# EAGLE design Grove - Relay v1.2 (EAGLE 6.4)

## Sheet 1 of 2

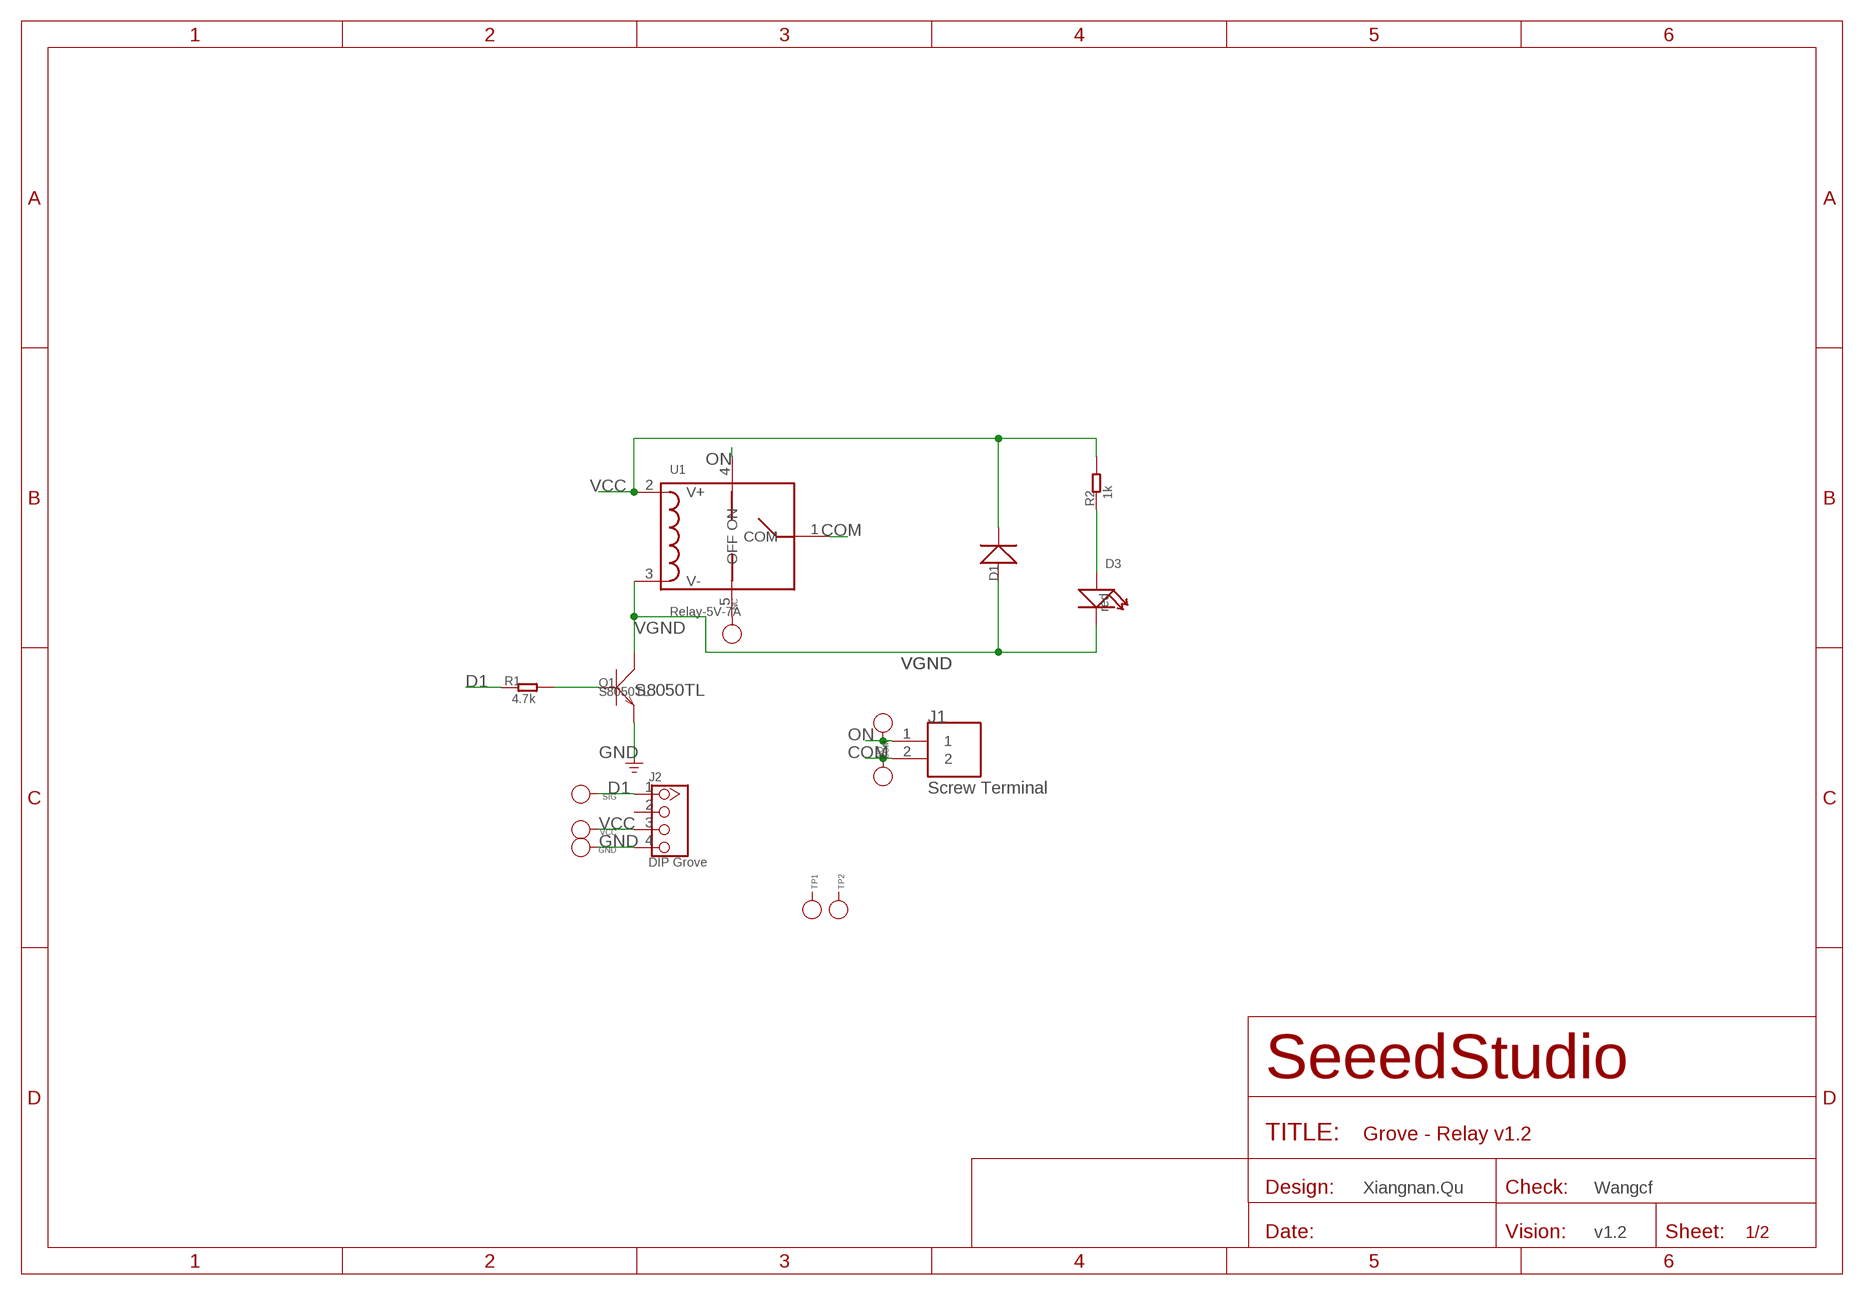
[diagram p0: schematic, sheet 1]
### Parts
COM  PAD-TEST-POINT'4545'  [TP_4545]
D1  D'1N4148-SMD'  [LL-34]
D3  red  LED'0603'  [LED-0603]
GND  PAD-TEST-POINT'4545'  [TP_4545]
J1  Screw Terminal  CON2  [CON2]
J2  DIP Grove  TWIG_2.0  [2.0_1X4]
NC  PAD-TEST-POINT'4545'  [TP_4545]
NO  PAD-TEST-POINT'4545'  [TP_4545]
Q1  S8050TL  TRANSISTOR-NPN-SOT23  [SOT23]
R1  4.7k  R-0603  [R0603]
R2  1k  R-0603  [R0603]
SIG  PAD-TEST-POINT'4545'  [TP_4545]
TP1  PAD-TEST-POINT'4545'  [TP_4545]
TP2  PAD-TEST-POINT'4545'  [TP_4545]
U1  Relay-5V-7A  RELAY  [RELAY]
VCC  PAD-TEST-POINT'4545'  [TP_4545]

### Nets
COM: COM.T J1.2 U1.1(COM)
D1: J2.1 R1.1 SIG.T
GND: GND.T J2.4 Q1.2(E)
N$1: D3.+ R2.1
N$2: Q1.1(B) R1.2
N$3: NC.T U1.5(OFF)
ON: J1.1 NO.T U1.4(ON)
VCC: D1.C(-) J2.3 R2.2 U1.2(V+) VCC.T
VGND: D1.A(+) D3.- Q1.3(C) U1.3(V-)
Unconnected: J2.2 TP1.T TP2.T

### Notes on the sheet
- S8050TL
- Xiangnan.Qu | Wangcf
- v1.2

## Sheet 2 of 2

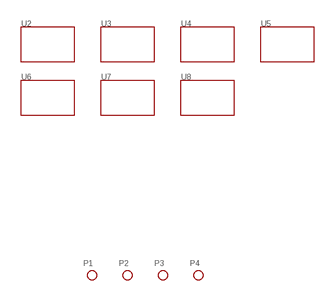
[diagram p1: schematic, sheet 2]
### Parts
P1  PAD-MARK  [ROUND-MARK-1.0]
P2  PAD-MARK  [ROUND-MARK-1.0]
P3  PAD-MARK  [ROUND-MARK-1.0]
P4  PAD-MARK  [ROUND-MARK-1.0]
U2  TWIG'2U'  [GROVE-TEST-PLATFORM]
U3  TWIG'2U'  [GROVE-TEST-PLATFORM]
U4  TWIG'2U'  [GROVE-TEST-PLATFORM]
U5  TWIG'2U'  [GROVE-TEST-PLATFORM]
U6  TWIG'2U'  [GROVE-TEST-PLATFORM]
U7  TWIG'2U'  [GROVE-TEST-PLATFORM]
U8  TWIG'2U'  [GROVE-TEST-PLATFORM]

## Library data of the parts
COM GND NC NO SIG TP1 TP2 VCC = Discrete:PAD-TEST-POINT; PARTNO: DNP
D1 = Discrete:D*
D3 = Discrete:LED*
J1 = seeedleo:CON2
J2 = CONNECTER:TWIG_2.0
P1-P4 = Discrete:PAD-MARK; PARTNO: DNP
Q1 = Discrete:TRANSISTOR-NPN*: NPN audion
R1 R2 = Discrete:R*
U1 = Seeed:RELAY
U2-U8 = template:TWIG

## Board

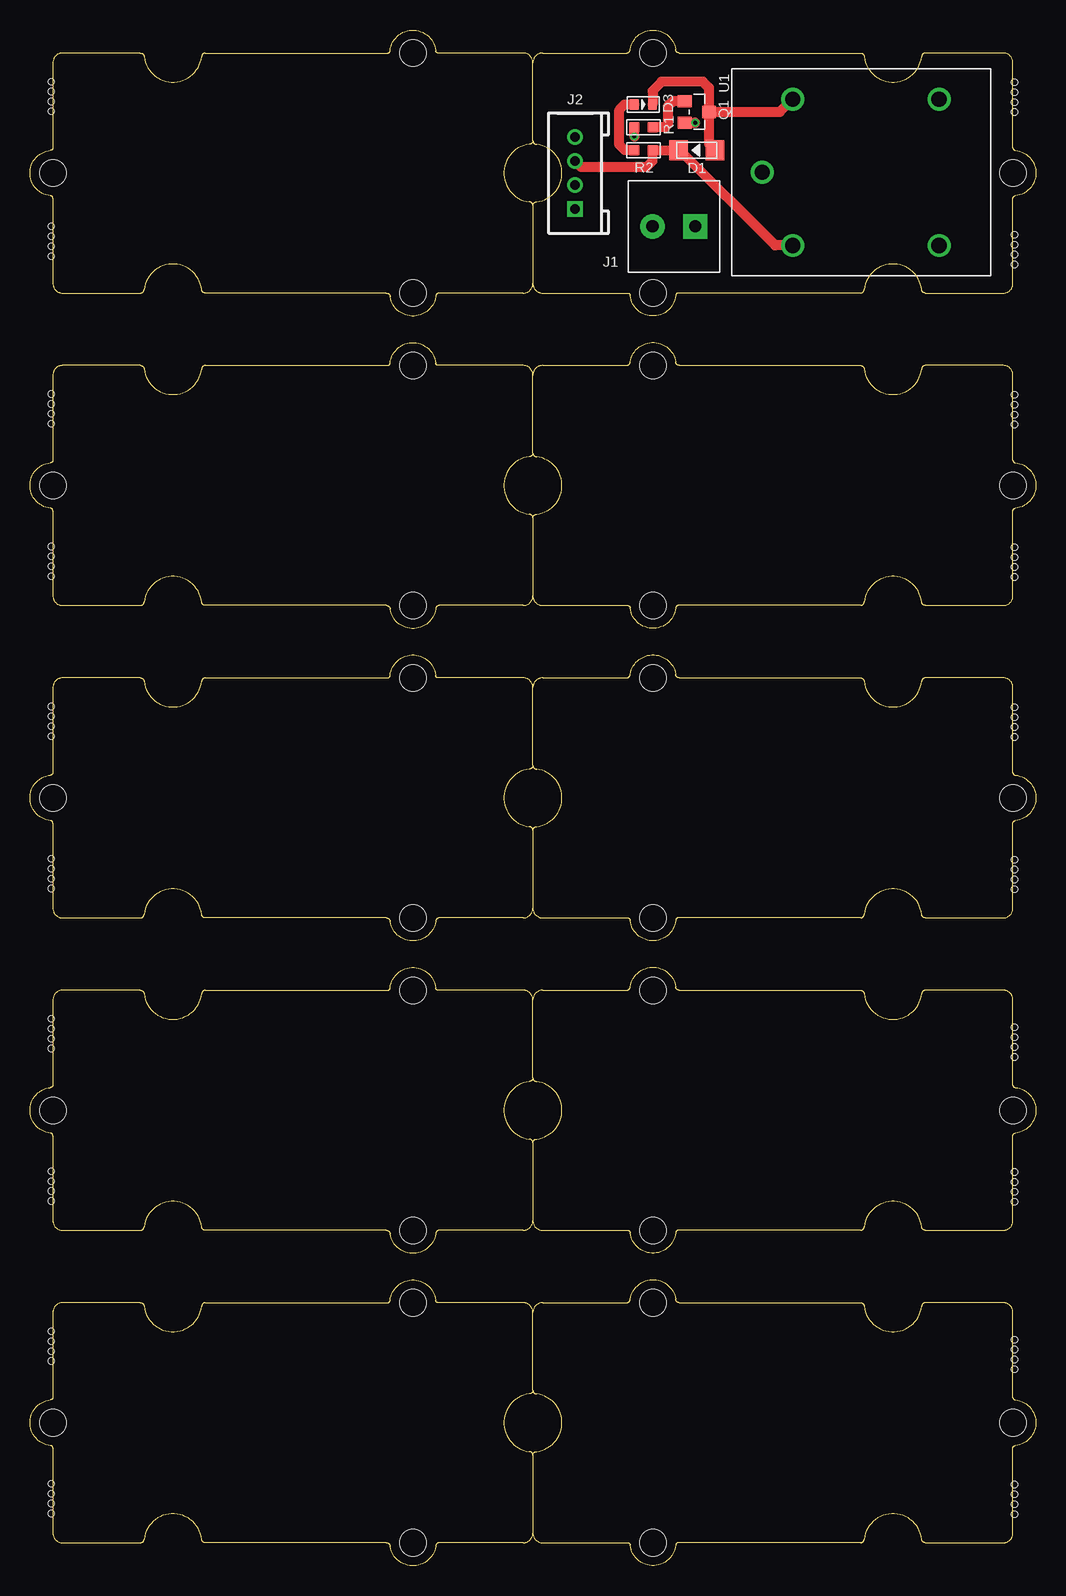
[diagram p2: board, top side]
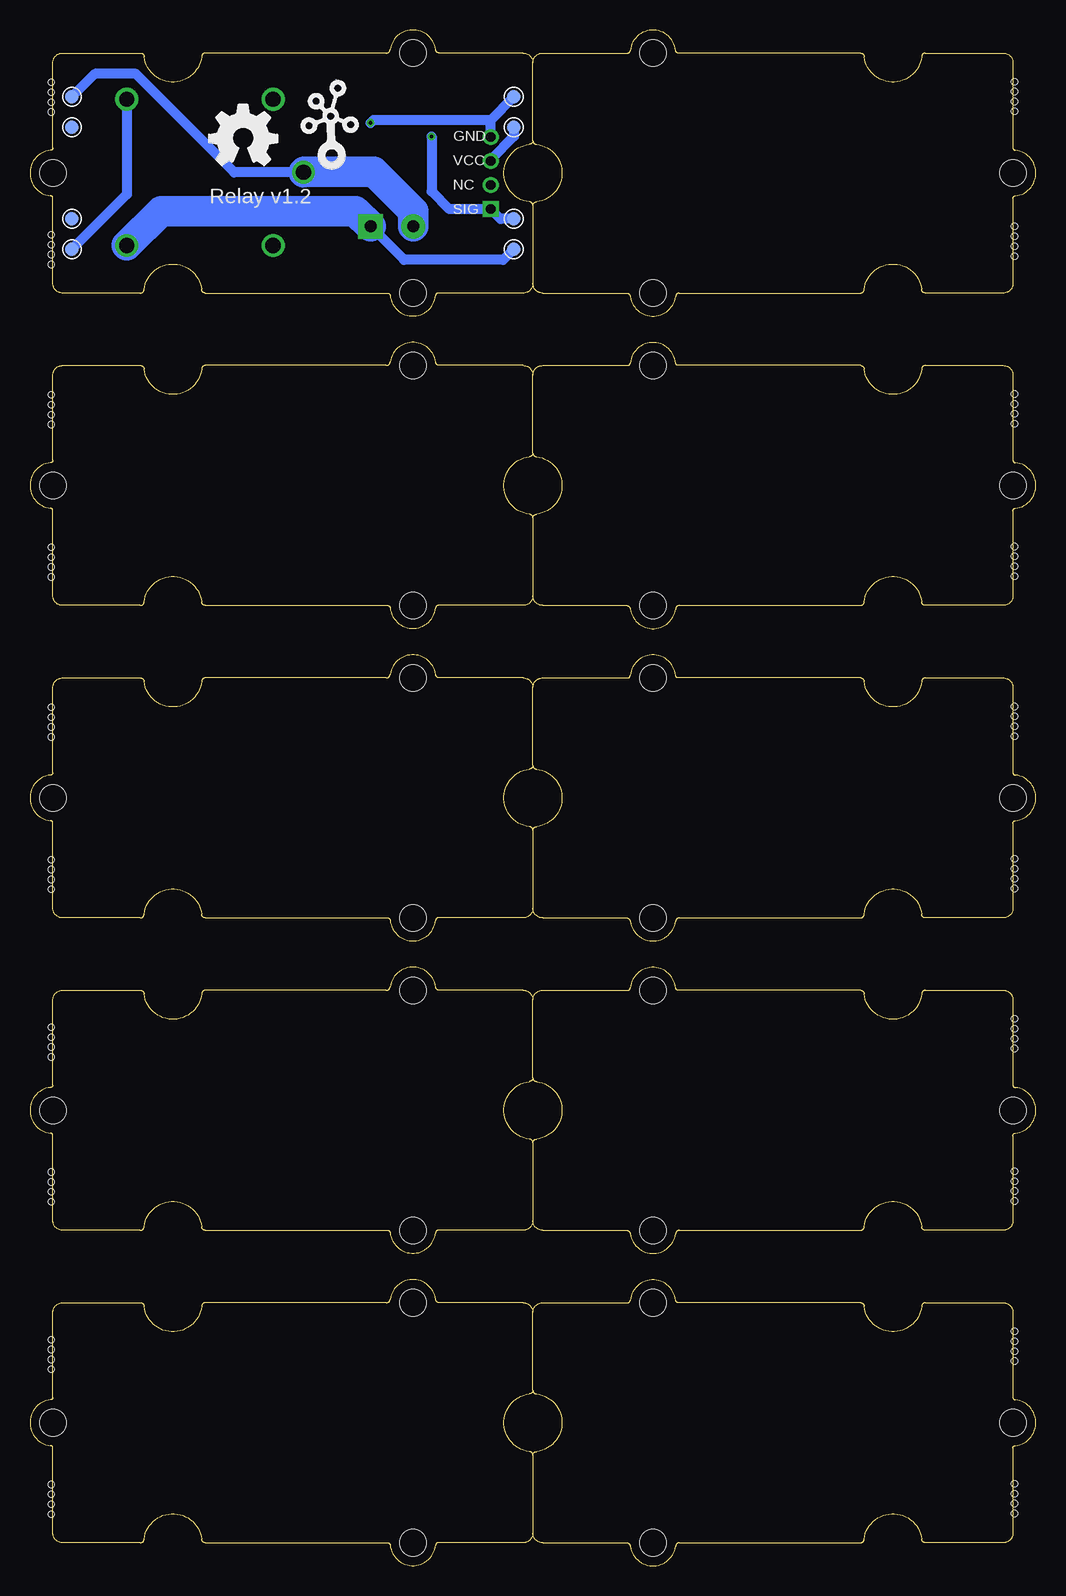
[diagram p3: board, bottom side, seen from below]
Size 83.82 x 127.98 mm. Coordinates in mm from the lower left corner, seen from the top.
Copper layers (1*16): Top 0.035mm / dielectric 1.5mm / Bottom 0.035mm
Design rules "default": minimum track width 6mil, minimum drill 12mil, track to track 6mil, track to pad 6mil, pad to pad 6mil, via to via 6mil, smd to smd 0mil, copper to edge 10mil, drill to drill 10mil, minimum pad ring 10mil, minimum via ring 6mil, stop-mask expansion 2mil, vias tented up to drill 100mil, thermal gap 10mil
Holes 0.5 mm at 1.78,32.88 1.78,30.4 1.78,31.23 1.78,32.05 1.78,45.58 1.78,43.1 1.78,43.93 1.78,44.75 1.78,58.91 1.78,56.43 1.78,57.26 1.78,58.09 1.78,71.61 1.78,69.13 1.78,69.96 1.78,70.79 1.78,84.95 1.78,82.47 1.78,83.3 1.78,84.12 1.78,97.65 1.78,95.17 1.78,96 1.78,96.82 1.78,111.62 1.78,109.14 1.78,109.97 1.78,110.79 1.78,123.68 1.78,121.2 1.78,122.03 1.78,122.86 82.04,121.14 82.04,123.62 82.04,122.79 82.04,121.97 82.04,108.44 82.04,110.92 82.04,110.09 82.04,109.27 82.04,95.11 82.04,97.58 82.04,96.76 82.04,95.93 82.04,82.41 82.04,84.88 82.04,84.06 82.04,83.23 82.04,69.07 82.04,71.55 82.04,70.72 82.04,69.9 82.04,56.37 82.04,58.85 82.04,58.02 82.04,57.2 82.04,42.4 82.04,44.88 82.04,44.05 82.04,43.23 82.04,30.34 82.04,32.81 82.04,31.99 82.04,31.16 1.78,6.84 1.78,4.36 1.78,5.19 1.78,6.02 1.78,19.54 1.78,17.06 1.78,17.89 1.78,18.72 82.04,16.37 82.04,18.84 82.04,18.02 82.04,17.19 82.04,4.3 82.04,6.78 82.04,5.95 82.04,5.13
Holes 1.91 mm at -4.13,2.4 87.95,2.4 87.95,125.59 -4.13,125.59

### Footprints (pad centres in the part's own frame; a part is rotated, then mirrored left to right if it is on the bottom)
TP_4545 = smd 1.143 x 1.143: T 0,0
LL-34 = smd 1.524 x 1.676: A -1.524,0; C 1.524,0
LED-0603 = smd 0.762 x 0.889: + -0.762,0; - 0.762,0
CON2 = drill 1.016 pad 2.032 square: 1 0,1.778 | drill 1.016 pad 2.032: 2 0,-1.778
2.0_1X4 = drill 0.8 pad 1.27 square: 1 -3,0 | drill 0.8 pad 1.27: 2 -1,0; 3 1,0; 4 3,0
ROUND-MARK-1.0 = smd 1.016 x 1.016: P$1 0,0
SOT23 = smd 1.016 x 1.143: 1 -0.889,-1.016; 2 0.889,-1.016; 3 0,1.016
R0603 = smd 0.889 x 0.889: 1 -0.762,0; 2 0.762,0
RELAY = drill 1.27: 1 -2.54,-6.096; 2 0,-12.192; 3 0,0; 4 12.192,-12.192; 5 12.192,0
GROVE-TEST-PLATFORM = hole 2.2: -10,-10; -10,10; 20,0

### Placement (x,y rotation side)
COM  80.33,122.41 0 bottom
D1  55.56,117.97 180 top
D3  51.12,121.78 0 top
GND  43.5,122.41 0 bottom
J1  53.66,111.62 270 top
J2  45.43,116.06 90 top
NC  80.33,109.71 0 bottom
NO  43.5,109.71 0 bottom
P1  not placed on the board
P2  not placed on the board
P3  not placed on the board
P4  not placed on the board
Q1  55.58,121.15 270 top
R1  51.12,119.87 0 top
R2  51.12,117.97 0 top
SIG  43.5,112.25 0 bottom
TP1  80.33,119.87 0 bottom
TP2  80.33,112.25 0 bottom
U1  63.56,122.22 0 top
U2  61.91,37.96 0 top
U3  21.91,37.96 180 top
U4  61.91,63.99 0 top
U5  21.91,63.99 180 top
U6  61.91,90.03 0 top
U7  21.91,90.03 180 top
U8  21.91,116.06 180 top
U10  [GROVE-TEST-PLATFORM]  61.91,11.92 0 top
U11  [GROVE-TEST-PLATFORM]  21.91,11.92 180 top
U$2  [OSHW_FILLX200_NOTEXT]  68.9,116.7 0 bottom
U$3  [GROVE-TEST-PLATFORM]  61.91,116.06 0 top
U$5  [TWIGLOGO]  58.74,117.33 0 bottom
VCC  43.5,119.87 0 bottom

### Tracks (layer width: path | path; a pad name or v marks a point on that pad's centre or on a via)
COM
  Bottom 0.813: U1.1 66.8,116.13 74.99,124.32 78.42,124.32 COM.T
  Bottom 2.54: J1.2 51.88,112.89 55.18,116.19 60.96,116.19 U1.1
D1  (via drill 0.3 pad 0.64)
  Top 0.813: v50.36,119.11 R1.1
  Bottom 0.813: SIG.T 44.62,112.25 J2.1 48.88,113.06 50.36,114.54 v50.36,119.11
GND  (via drill 0.3 pad 0.64)
  Top 0.813: Q1.2 55.42,120.27 v55.44,120.25
  Bottom 0.813: 45.43,120.48 J2.4 45.48,119.11 | 45.43,120.48 GND.T | 45.43,120.48 55.21,120.48 v55.44,120.25
N$1
  Top 0.813: R2.1 49.55,117.97 49.11,118.41 49.11,121.32 49.56,121.78 D3.+
N$2
  Top 0.813: Q1.1 53.54,122.04 53.15,121.65 53.15,120.13 52.9,119.87 R1.2
N$3
  Bottom 0.813: NC.T 75.76,114.28 U1.5
ON
  Bottom 0.813: NO.T 44.39,108.82 52.64,108.82 J1.1
  Bottom 2.54: U1.4 72.9,112.89 56.71,112.89 J1.1
VCC
  Top 0.813: J2.3 45.9,116.58 51.38,116.58 51.88,117.08 R2.2 D1.C 54.04,118.09 62.1,110.03 U1.2
  Bottom 0.813: VCC.T 43.5,119.11 45.4,117.2 45.4,117.09 J2.3
VGND
  Top 0.813: D3.- 51.88,122.92 52.64,123.68 56.07,123.68 56.58,123.17 56.58,121.17 | 56.58,121.17 Q1.3 62.5,121.15 U1.3 | 56.58,121.17 56.58,118.47 D1.A

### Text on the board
bPlace: GND | VCC | NC | SIG | Relay v1.2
